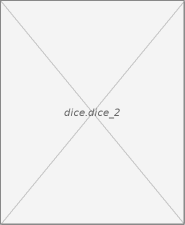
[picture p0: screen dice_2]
VISUALIZATION dice_2  // 185x225
VAR_IN_OUT
VAR_IN_OUT
	
END_VAR
    Image (0,0 185x225), image: dice.dice_2
END_VISUALIZATION
